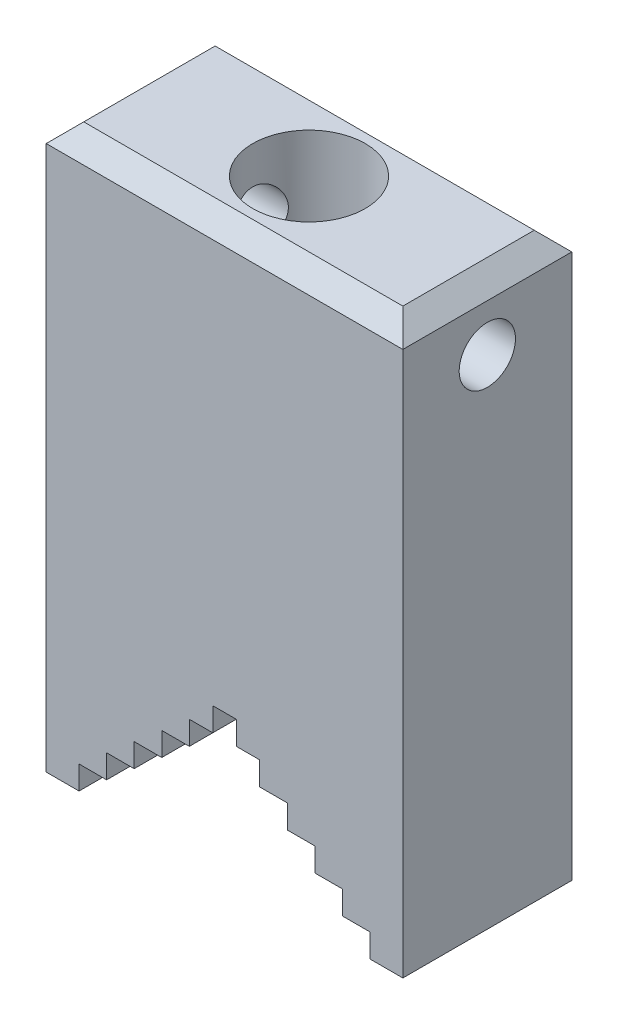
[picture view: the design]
ISO-10303-21;
HEADER;
FILE_DESCRIPTION(('STEP AP214'),'2;1');
FILE_NAME('part.step','',(''),(''),'','','');
FILE_SCHEMA(('AUTOMOTIVE_DESIGN { 1 0 10303 214 1 1 1 1 }'));
ENDSEC;
DATA;
#1=APPLICATION_CONTEXT('core data for automotive mechanical design processes');
#2=APPLICATION_PROTOCOL_DEFINITION('international standard','automotive_design',2000,#1);
#3=PRODUCT_CONTEXT('',#1,'mechanical');
#4=PRODUCT('Part','Part','',(#3));
#5=PRODUCT_RELATED_PRODUCT_CATEGORY('part','',(#4));
#6=PRODUCT_DEFINITION_FORMATION('','',#4);
#7=PRODUCT_DEFINITION_CONTEXT('part definition',#1,'design');
#8=PRODUCT_DEFINITION('design','',#6,#7);
#9=PRODUCT_DEFINITION_SHAPE('','',#8);
#10=(LENGTH_UNIT() NAMED_UNIT(*) SI_UNIT(.MILLI.,.METRE.));
#11=(NAMED_UNIT(*) PLANE_ANGLE_UNIT() SI_UNIT($,.RADIAN.));
#12=(NAMED_UNIT(*) SI_UNIT($,.STERADIAN.) SOLID_ANGLE_UNIT());
#13=UNCERTAINTY_MEASURE_WITH_UNIT(LENGTH_MEASURE(1.E-05),#10,'distance_accuracy_value','');
#14=(GEOMETRIC_REPRESENTATION_CONTEXT(3) GLOBAL_UNCERTAINTY_ASSIGNED_CONTEXT((#13)) GLOBAL_UNIT_ASSIGNED_CONTEXT((#10,
#11,#12)) REPRESENTATION_CONTEXT('',''));
#15=CARTESIAN_POINT('',(0.,0.,0.));
#16=DIRECTION('',(0.,0.,1.));
#17=DIRECTION('',(1.,0.,0.));
#18=AXIS2_PLACEMENT_3D('',#15,#16,#17);
#19=CARTESIAN_POINT('',(-19.,23.,0.));
#20=DIRECTION('',(1.,0.,0.));
#21=DIRECTION('',(0.,1.,0.));
#22=AXIS2_PLACEMENT_3D('',#19,#20,#21);
#23=CYLINDRICAL_SURFACE('',#22,3.);
#24=CARTESIAN_POINT('',(-6.,26.,0.));
#25=CARTESIAN_POINT('',(-5.99999934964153,25.9999991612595,0.07889414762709));
#26=CARTESIAN_POINT('',(-5.99843869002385,25.9968820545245,0.15779662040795));
#27=CARTESIAN_POINT('',(-5.99224358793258,25.98446072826,0.315001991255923));
#28=CARTESIAN_POINT('',(-5.98760776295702,25.9751537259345,0.393304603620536));
#29=CARTESIAN_POINT('',(-5.96921978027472,25.9380421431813,0.626628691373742));
#30=CARTESIAN_POINT('',(-5.95098734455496,25.9010471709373,0.779952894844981));
#31=CARTESIAN_POINT('',(-5.90448966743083,25.8044182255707,1.07683586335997));
#32=CARTESIAN_POINT('',(-5.87626344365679,25.7448722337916,1.22043005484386));
#33=CARTESIAN_POINT('',(-5.81237302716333,25.6052887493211,1.49540820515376));
#34=CARTESIAN_POINT('',(-5.77670942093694,25.5252528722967,1.62679312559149));
#35=CARTESIAN_POINT('',(-5.69868752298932,25.3414460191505,1.88252701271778));
#36=CARTESIAN_POINT('',(-5.65605474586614,25.2365320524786,2.0059694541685));
#37=CARTESIAN_POINT('',(-5.56980033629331,25.0084440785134,2.23433451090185));
#38=CARTESIAN_POINT('',(-5.5261779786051,24.8852562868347,2.3392430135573));
#39=CARTESIAN_POINT('',(-5.43896347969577,24.6125156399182,2.53576864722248));
#40=CARTESIAN_POINT('',(-5.39563602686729,24.4616590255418,2.62572411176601));
#41=CARTESIAN_POINT('',(-5.33782449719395,24.2240491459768,2.7403403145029));
#42=CARTESIAN_POINT('',(-5.31974570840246,24.1429290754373,2.77516786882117));
#43=CARTESIAN_POINT('',(-5.28665768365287,23.9773994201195,2.83769299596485));
#44=CARTESIAN_POINT('',(-5.27164663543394,23.8929918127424,2.86539478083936));
#45=CARTESIAN_POINT('',(-5.24610341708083,23.7266042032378,2.91188280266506));
#46=CARTESIAN_POINT('',(-5.23535838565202,23.6447772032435,2.93110042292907));
#47=CARTESIAN_POINT('',(-5.21757784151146,23.4794450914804,2.9626355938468));
#48=CARTESIAN_POINT('',(-5.21054036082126,23.3959408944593,2.97495680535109));
#49=CARTESIAN_POINT('',(-5.20047756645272,23.2279936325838,2.99251382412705));
#50=CARTESIAN_POINT('',(-5.19744983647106,23.1435511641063,2.99775389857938));
#51=CARTESIAN_POINT('',(-5.19552555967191,22.9745063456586,3.00108452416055));
#52=CARTESIAN_POINT('',(-5.19662861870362,22.8899040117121,2.9991757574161));
#53=CARTESIAN_POINT('',(-5.20534668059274,22.6572461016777,2.98404973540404));
#54=CARTESIAN_POINT('',(-5.21726794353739,22.5097558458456,2.96335042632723));
#55=CARTESIAN_POINT('',(-5.25228182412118,22.2208063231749,2.90082280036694));
#56=CARTESIAN_POINT('',(-5.2753780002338,22.0793489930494,2.85898775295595));
#57=CARTESIAN_POINT('',(-5.33062568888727,21.8023203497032,2.75462843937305));
#58=CARTESIAN_POINT('',(-5.36297559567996,21.6669628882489,2.69164495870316));
#59=CARTESIAN_POINT('',(-5.43310175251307,21.408095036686,2.54712530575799));
#60=CARTESIAN_POINT('',(-5.47088043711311,21.2845900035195,2.46558080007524));
#61=CARTESIAN_POINT('',(-5.55339485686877,21.0364369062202,2.27419808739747));
#62=CARTESIAN_POINT('',(-5.59840533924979,20.9136295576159,2.16208335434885));
#63=CARTESIAN_POINT('',(-5.6864286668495,20.6877935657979,1.91866675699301));
#64=CARTESIAN_POINT('',(-5.72944054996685,20.5847743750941,1.78735577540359));
#65=CARTESIAN_POINT('',(-5.81105962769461,20.3969430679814,1.50154951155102));
#66=CARTESIAN_POINT('',(-5.84936952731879,20.3131985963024,1.3462607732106));
#67=CARTESIAN_POINT('',(-5.91473643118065,20.1737088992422,1.02139864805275));
#68=CARTESIAN_POINT('',(-5.94180236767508,20.1179414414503,0.851836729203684));
#69=CARTESIAN_POINT('',(-5.97973001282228,20.0405737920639,0.518299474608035));
#70=CARTESIAN_POINT('',(-5.99174814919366,20.0165262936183,0.355024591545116));
#71=CARTESIAN_POINT('',(-6.00219040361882,19.9956058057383,0.0263387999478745));
#72=CARTESIAN_POINT('',(-6.00062096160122,19.9987199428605,-0.139071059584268));
#73=CARTESIAN_POINT('',(-5.98473576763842,20.0306200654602,-0.453698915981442));
#74=CARTESIAN_POINT('',(-5.97141737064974,20.0573975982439,-0.603178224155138));
#75=CARTESIAN_POINT('',(-5.93466513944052,20.1327142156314,-0.895220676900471));
#76=CARTESIAN_POINT('',(-5.91123019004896,20.1812556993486,-1.03778305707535));
#77=CARTESIAN_POINT('',(-5.85552754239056,20.2999953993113,-1.31666582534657));
#78=CARTESIAN_POINT('',(-5.82302645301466,20.3707731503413,-1.45269119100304));
#79=CARTESIAN_POINT('',(-5.75231922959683,20.5313226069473,-1.71138408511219));
#80=CARTESIAN_POINT('',(-5.71411066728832,20.6211024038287,-1.83404588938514));
#81=CARTESIAN_POINT('',(-5.63124663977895,20.8272812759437,-2.07530306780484));
#82=CARTESIAN_POINT('',(-5.58632654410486,20.9454286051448,-2.19231623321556));
#83=CARTESIAN_POINT('',(-5.49787174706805,21.1997754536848,-2.40556896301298));
#84=CARTESIAN_POINT('',(-5.45433802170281,21.3359873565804,-2.50179415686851));
#85=CARTESIAN_POINT('',(-5.3715357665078,21.6309309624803,-2.675123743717));
#86=CARTESIAN_POINT('',(-5.33257588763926,21.7904337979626,-2.75107648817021));
#87=CARTESIAN_POINT('',(-5.26722216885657,22.1225302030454,-2.87424847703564));
#88=CARTESIAN_POINT('',(-5.24081214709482,22.2951065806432,-2.92150474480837));
#89=CARTESIAN_POINT('',(-5.2068450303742,22.6307306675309,-2.98158506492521));
#90=CARTESIAN_POINT('',(-5.19772150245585,22.7931027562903,-2.997278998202));
#91=CARTESIAN_POINT('',(-5.19496064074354,23.1183412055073,-3.00206745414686));
#92=CARTESIAN_POINT('',(-5.20131659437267,23.2812073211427,-2.99117350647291));
#93=CARTESIAN_POINT('',(-5.227135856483,23.5864504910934,-2.94577840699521));
#94=CARTESIAN_POINT('',(-5.24529281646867,23.7293013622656,-2.91362505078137));
#95=CARTESIAN_POINT('',(-5.29113050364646,24.0074244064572,-2.82952596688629));
#96=CARTESIAN_POINT('',(-5.3188142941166,24.1426941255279,-2.77757387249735));
#97=CARTESIAN_POINT('',(-5.38285583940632,24.4118743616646,-2.65144766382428));
#98=CARTESIAN_POINT('',(-5.41967139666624,24.5450829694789,-2.57601505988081));
#99=CARTESIAN_POINT('',(-5.49706022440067,24.7978243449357,-2.40645126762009));
#100=CARTESIAN_POINT('',(-5.53763544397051,24.9173499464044,-2.31231035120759));
#101=CARTESIAN_POINT('',(-5.62386853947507,25.1544228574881,-2.094616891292));
#102=CARTESIAN_POINT('',(-5.66954494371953,25.2699651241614,-1.96888052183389));
#103=CARTESIAN_POINT('',(-5.75633712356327,25.478801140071,-1.69843715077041));
#104=CARTESIAN_POINT('',(-5.79745043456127,25.5720828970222,-1.55371998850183));
#105=CARTESIAN_POINT('',(-5.85251406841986,25.6931781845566,-1.32452333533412));
#106=CARTESIAN_POINT('',(-5.86982524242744,25.7305202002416,-1.24575314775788));
#107=CARTESIAN_POINT('',(-5.90168845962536,25.7983616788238,-1.0847972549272));
#108=CARTESIAN_POINT('',(-5.91624185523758,25.8288644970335,-1.00261324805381));
#109=CARTESIAN_POINT('',(-5.94212690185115,25.8826072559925,-0.835616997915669));
#110=CARTESIAN_POINT('',(-5.95346557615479,25.905863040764,-0.750810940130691));
#111=CARTESIAN_POINT('',(-5.97260771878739,25.9448825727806,-0.579142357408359));
#112=CARTESIAN_POINT('',(-5.98041334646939,25.9606508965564,-0.492281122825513));
#113=CARTESIAN_POINT('',(-5.99085829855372,25.9816846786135,-0.337824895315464));
#114=CARTESIAN_POINT('',(-5.99428035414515,25.988546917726,-0.270495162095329));
#115=CARTESIAN_POINT('',(-5.99885151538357,25.997705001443,-0.13544567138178));
#116=CARTESIAN_POINT('',(-6.00000055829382,26.0000007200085,-0.0677259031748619));
#117=CARTESIAN_POINT('',(-6.,26.,0.));
#118=B_SPLINE_CURVE_WITH_KNOTS('',3,(#24,#25,#26,#27,#28,#29,#30,#31,#32,#33,#34,#35,#36,#37,
#38,#39,#40,#41,#42,#43,#44,#45,#46,#47,#48,#49,#50,#51,#52,#53,#54,#55,#56,#57,#58,#59,#60,#61,
#62,#63,#64,#65,#66,#67,#68,#69,#70,#71,#72,#73,#74,#75,#76,#77,#78,#79,#80,#81,#82,#83,#84,#85,
#86,#87,#88,#89,#90,#91,#92,#93,#94,#95,#96,#97,#98,#99,#100,#101,#102,#103,#104,#105,#106,#107,
#108,#109,#110,#111,#112,#113,#114,#115,#116,#117),.UNSPECIFIED.,.T.,.F.,(4,2,2,2,2,2,2,2,2,2,2,
2,2,2,2,2,2,2,2,2,2,2,2,2,2,2,2,2,2,2,2,2,2,2,2,2,2,2,2,2,2,2,2,2,2,2,4),(0.,0.236611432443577,
0.473329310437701,0.947100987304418,1.41904300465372,1.89094781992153,2.39140181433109,
2.89223525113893,3.4319083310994,3.70192714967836,3.97178599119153,4.22563720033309,
4.4793535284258,4.73291689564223,4.98645606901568,5.4323867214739,5.87845946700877,
6.33492255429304,6.79159098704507,7.30616358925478,7.82098138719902,8.35970601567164,
8.89800185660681,9.39171406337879,9.8851922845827,10.3404225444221,10.7957029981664,
11.2640010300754,11.7324988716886,12.2470036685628,12.7618630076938,13.3016558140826,
13.8407507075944,14.3280945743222,14.8152271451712,15.2559532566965,15.6968212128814,
16.1673090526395,16.6380421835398,17.1659726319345,17.6941868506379,17.9605054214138,
18.2266930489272,18.4922945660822,18.7577335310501,18.9608446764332,19.1639614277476),.UNSPECIFIED.);
#119=CARTESIAN_POINT('',(-6.,26.,0.));
#120=VERTEX_POINT('',#119);
#121=EDGE_CURVE('E270',#120,#120,#118,.T.);
#122=ORIENTED_EDGE('',*,*,#121,.T.);
#123=EDGE_LOOP('',(#122));
#124=FACE_BOUND('',#123,.T.);
#125=CARTESIAN_POINT('',(-19.,23.,0.));
#126=DIRECTION('',(1.,0.,0.));
#127=DIRECTION('',(0.,1.,0.));
#128=AXIS2_PLACEMENT_3D('',#125,#126,#127);
#129=CIRCLE('',#128,3.);
#130=CARTESIAN_POINT('',(-19.,26.,0.));
#131=VERTEX_POINT('',#130);
#132=EDGE_CURVE('E269',#131,#131,#129,.T.);
#133=ORIENTED_EDGE('',*,*,#132,.F.);
#134=EDGE_LOOP('',(#133));
#135=FACE_BOUND('',#134,.T.);
#136=ADVANCED_FACE('F26',(#124,#135),#23,.F.);
#137=CARTESIAN_POINT('',(-19.,30.,9.));
#138=DIRECTION('',(1.,0.,0.));
#139=DIRECTION('',(0.,1.,0.));
#140=AXIS2_PLACEMENT_3D('',#137,#138,#139);
#141=PLANE('',#140);
#142=ORIENTED_EDGE('',*,*,#132,.T.);
#143=EDGE_LOOP('',(#142));
#144=FACE_BOUND('',#143,.T.);
#145=DIRECTION('',(0.,-1.,0.));
#146=VECTOR('',#145,1.);
#147=CARTESIAN_POINT('',(-19.,30.,9.));
#148=LINE('',#147,#146);
#149=CARTESIAN_POINT('',(-19.,28.,9.));
#150=VERTEX_POINT('',#149);
#151=CARTESIAN_POINT('',(-19.,-30.,9.));
#152=VERTEX_POINT('',#151);
#153=EDGE_CURVE('E333',#150,#152,#148,.T.);
#154=ORIENTED_EDGE('',*,*,#153,.F.);
#155=DIRECTION('',(0.,0.,-1.));
#156=VECTOR('',#155,1.);
#157=CARTESIAN_POINT('',(-19.,28.,9.));
#158=LINE('',#157,#156);
#159=CARTESIAN_POINT('',(-19.,28.,-9.));
#160=VERTEX_POINT('',#159);
#161=EDGE_CURVE('E465',#150,#160,#158,.T.);
#162=ORIENTED_EDGE('',*,*,#161,.T.);
#163=DIRECTION('',(0.,-1.,0.));
#164=VECTOR('',#163,1.);
#165=CARTESIAN_POINT('',(-19.,30.,-9.));
#166=LINE('',#165,#164);
#167=CARTESIAN_POINT('',(-19.,-30.,-9.));
#168=VERTEX_POINT('',#167);
#169=EDGE_CURVE('E273',#160,#168,#166,.T.);
#170=ORIENTED_EDGE('',*,*,#169,.T.);
#171=DIRECTION('',(0.,0.,-1.));
#172=VECTOR('',#171,1.);
#173=CARTESIAN_POINT('',(-19.,-30.,9.));
#174=LINE('',#173,#172);
#175=EDGE_CURVE('E462',#152,#168,#174,.T.);
#176=ORIENTED_EDGE('',*,*,#175,.F.);
#177=EDGE_LOOP('',(#154,#162,#170,#176));
#178=FACE_BOUND('',#177,.T.);
#179=ADVANCED_FACE('F28',(#144,#178),#141,.F.);
#180=CARTESIAN_POINT('',(-19.,-30.,9.));
#181=DIRECTION('',(0.,1.,0.));
#182=DIRECTION('',(0.,0.,1.));
#183=AXIS2_PLACEMENT_3D('',#180,#181,#182);
#184=PLANE('',#183);
#185=DIRECTION('',(1.,0.,0.));
#186=VECTOR('',#185,1.);
#187=CARTESIAN_POINT('',(-19.,-30.,-9.));
#188=LINE('',#187,#186);
#189=CARTESIAN_POINT('',(-15.5,-30.,-9.));
#190=VERTEX_POINT('',#189);
#191=EDGE_CURVE('E281',#168,#190,#188,.T.);
#192=ORIENTED_EDGE('',*,*,#191,.T.);
#193=DIRECTION('',(0.,0.,-1.));
#194=VECTOR('',#193,1.);
#195=CARTESIAN_POINT('',(-15.5,-30.,9.));
#196=LINE('',#195,#194);
#197=CARTESIAN_POINT('',(-15.5,-30.,9.));
#198=VERTEX_POINT('',#197);
#199=EDGE_CURVE('E459',#198,#190,#196,.T.);
#200=ORIENTED_EDGE('',*,*,#199,.F.);
#201=DIRECTION('',(1.,0.,0.));
#202=VECTOR('',#201,1.);
#203=CARTESIAN_POINT('',(-19.,-30.,9.));
#204=LINE('',#203,#202);
#205=EDGE_CURVE('E335',#152,#198,#204,.T.);
#206=ORIENTED_EDGE('',*,*,#205,.F.);
#207=ORIENTED_EDGE('',*,*,#175,.T.);
#208=EDGE_LOOP('',(#192,#200,#206,#207));
#209=FACE_BOUND('',#208,.T.);
#210=ADVANCED_FACE('F248',(#209),#184,.F.);
#211=CARTESIAN_POINT('',(-15.5,-30.,9.));
#212=DIRECTION('',(-1.,0.,0.));
#213=DIRECTION('',(0.,-1.,0.));
#214=AXIS2_PLACEMENT_3D('',#211,#212,#213);
#215=PLANE('',#214);
#216=DIRECTION('',(0.,1.,0.));
#217=VECTOR('',#216,1.);
#218=CARTESIAN_POINT('',(-15.5,-30.,-9.));
#219=LINE('',#218,#217);
#220=CARTESIAN_POINT('',(-15.5,-27.5,-9.));
#221=VERTEX_POINT('',#220);
#222=EDGE_CURVE('E283',#190,#221,#219,.T.);
#223=ORIENTED_EDGE('',*,*,#222,.T.);
#224=DIRECTION('',(0.,0.,-1.));
#225=VECTOR('',#224,1.);
#226=CARTESIAN_POINT('',(-15.5,-27.5,9.));
#227=LINE('',#226,#225);
#228=CARTESIAN_POINT('',(-15.5,-27.5,9.));
#229=VERTEX_POINT('',#228);
#230=EDGE_CURVE('E456',#229,#221,#227,.T.);
#231=ORIENTED_EDGE('',*,*,#230,.F.);
#232=DIRECTION('',(0.,1.,0.));
#233=VECTOR('',#232,1.);
#234=CARTESIAN_POINT('',(-15.5,-30.,9.));
#235=LINE('',#234,#233);
#236=EDGE_CURVE('E337',#198,#229,#235,.T.);
#237=ORIENTED_EDGE('',*,*,#236,.F.);
#238=ORIENTED_EDGE('',*,*,#199,.T.);
#239=EDGE_LOOP('',(#223,#231,#237,#238));
#240=FACE_BOUND('',#239,.T.);
#241=ADVANCED_FACE('F618',(#240),#215,.F.);
#242=CARTESIAN_POINT('',(-15.5,-27.5,9.));
#243=DIRECTION('',(0.,1.,0.));
#244=DIRECTION('',(0.,0.,1.));
#245=AXIS2_PLACEMENT_3D('',#242,#243,#244);
#246=PLANE('',#245);
#247=DIRECTION('',(1.,0.,0.));
#248=VECTOR('',#247,1.);
#249=CARTESIAN_POINT('',(-15.5,-27.5,-9.));
#250=LINE('',#249,#248);
#251=CARTESIAN_POINT('',(-12.5625,-27.5,-9.));
#252=VERTEX_POINT('',#251);
#253=EDGE_CURVE('E285',#221,#252,#250,.T.);
#254=ORIENTED_EDGE('',*,*,#253,.T.);
#255=DIRECTION('',(0.,0.,-1.));
#256=VECTOR('',#255,1.);
#257=CARTESIAN_POINT('',(-12.5625,-27.5,9.));
#258=LINE('',#257,#256);
#259=CARTESIAN_POINT('',(-12.5625,-27.5,9.));
#260=VERTEX_POINT('',#259);
#261=EDGE_CURVE('E453',#260,#252,#258,.T.);
#262=ORIENTED_EDGE('',*,*,#261,.F.);
#263=DIRECTION('',(1.,0.,0.));
#264=VECTOR('',#263,1.);
#265=CARTESIAN_POINT('',(-15.5,-27.5,9.));
#266=LINE('',#265,#264);
#267=EDGE_CURVE('E339',#229,#260,#266,.T.);
#268=ORIENTED_EDGE('',*,*,#267,.F.);
#269=ORIENTED_EDGE('',*,*,#230,.T.);
#270=EDGE_LOOP('',(#254,#262,#268,#269));
#271=FACE_BOUND('',#270,.T.);
#272=ADVANCED_FACE('F614',(#271),#246,.F.);
#273=CARTESIAN_POINT('',(-12.5625,-27.5,9.));
#274=DIRECTION('',(-1.,0.,0.));
#275=DIRECTION('',(0.,0.,1.));
#276=AXIS2_PLACEMENT_3D('',#273,#274,#275);
#277=PLANE('',#276);
#278=DIRECTION('',(0.,1.,0.));
#279=VECTOR('',#278,1.);
#280=CARTESIAN_POINT('',(-12.5625,-27.5,-9.));
#281=LINE('',#280,#279);
#282=CARTESIAN_POINT('',(-12.5625,-25.,-9.));
#283=VERTEX_POINT('',#282);
#284=EDGE_CURVE('E287',#252,#283,#281,.T.);
#285=ORIENTED_EDGE('',*,*,#284,.T.);
#286=DIRECTION('',(0.,0.,-1.));
#287=VECTOR('',#286,1.);
#288=CARTESIAN_POINT('',(-12.5625,-25.,9.));
#289=LINE('',#288,#287);
#290=CARTESIAN_POINT('',(-12.5625,-25.,9.));
#291=VERTEX_POINT('',#290);
#292=EDGE_CURVE('E450',#291,#283,#289,.T.);
#293=ORIENTED_EDGE('',*,*,#292,.F.);
#294=DIRECTION('',(0.,1.,0.));
#295=VECTOR('',#294,1.);
#296=CARTESIAN_POINT('',(-12.5625,-27.5,9.));
#297=LINE('',#296,#295);
#298=EDGE_CURVE('E341',#260,#291,#297,.T.);
#299=ORIENTED_EDGE('',*,*,#298,.F.);
#300=ORIENTED_EDGE('',*,*,#261,.T.);
#301=EDGE_LOOP('',(#285,#293,#299,#300));
#302=FACE_BOUND('',#301,.T.);
#303=ADVANCED_FACE('F610',(#302),#277,.F.);
#304=CARTESIAN_POINT('',(-12.5625,-25.,9.));
#305=DIRECTION('',(0.,1.,0.));
#306=DIRECTION('',(0.,0.,1.));
#307=AXIS2_PLACEMENT_3D('',#304,#305,#306);
#308=PLANE('',#307);
#309=DIRECTION('',(1.,0.,0.));
#310=VECTOR('',#309,1.);
#311=CARTESIAN_POINT('',(-12.5625,-25.,-9.));
#312=LINE('',#311,#310);
#313=CARTESIAN_POINT('',(-9.625,-25.,-9.));
#314=VERTEX_POINT('',#313);
#315=EDGE_CURVE('E289',#283,#314,#312,.T.);
#316=ORIENTED_EDGE('',*,*,#315,.T.);
#317=DIRECTION('',(0.,0.,-1.));
#318=VECTOR('',#317,1.);
#319=CARTESIAN_POINT('',(-9.625,-25.,9.));
#320=LINE('',#319,#318);
#321=CARTESIAN_POINT('',(-9.625,-25.,9.));
#322=VERTEX_POINT('',#321);
#323=EDGE_CURVE('E447',#322,#314,#320,.T.);
#324=ORIENTED_EDGE('',*,*,#323,.F.);
#325=DIRECTION('',(1.,0.,0.));
#326=VECTOR('',#325,1.);
#327=CARTESIAN_POINT('',(-12.5625,-25.,9.));
#328=LINE('',#327,#326);
#329=EDGE_CURVE('E343',#291,#322,#328,.T.);
#330=ORIENTED_EDGE('',*,*,#329,.F.);
#331=ORIENTED_EDGE('',*,*,#292,.T.);
#332=EDGE_LOOP('',(#316,#324,#330,#331));
#333=FACE_BOUND('',#332,.T.);
#334=ADVANCED_FACE('F606',(#333),#308,.F.);
#335=CARTESIAN_POINT('',(-9.625,-25.,9.));
#336=DIRECTION('',(-1.,0.,0.));
#337=DIRECTION('',(0.,0.,1.));
#338=AXIS2_PLACEMENT_3D('',#335,#336,#337);
#339=PLANE('',#338);
#340=DIRECTION('',(0.,1.,0.));
#341=VECTOR('',#340,1.);
#342=CARTESIAN_POINT('',(-9.625,-25.,-9.));
#343=LINE('',#342,#341);
#344=CARTESIAN_POINT('',(-9.625,-22.5,-9.));
#345=VERTEX_POINT('',#344);
#346=EDGE_CURVE('E291',#314,#345,#343,.T.);
#347=ORIENTED_EDGE('',*,*,#346,.T.);
#348=DIRECTION('',(0.,0.,-1.));
#349=VECTOR('',#348,1.);
#350=CARTESIAN_POINT('',(-9.625,-22.5,9.));
#351=LINE('',#350,#349);
#352=CARTESIAN_POINT('',(-9.625,-22.5,9.));
#353=VERTEX_POINT('',#352);
#354=EDGE_CURVE('E444',#353,#345,#351,.T.);
#355=ORIENTED_EDGE('',*,*,#354,.F.);
#356=DIRECTION('',(0.,1.,0.));
#357=VECTOR('',#356,1.);
#358=CARTESIAN_POINT('',(-9.625,-25.,9.));
#359=LINE('',#358,#357);
#360=EDGE_CURVE('E345',#322,#353,#359,.T.);
#361=ORIENTED_EDGE('',*,*,#360,.F.);
#362=ORIENTED_EDGE('',*,*,#323,.T.);
#363=EDGE_LOOP('',(#347,#355,#361,#362));
#364=FACE_BOUND('',#363,.T.);
#365=ADVANCED_FACE('F602',(#364),#339,.F.);
#366=CARTESIAN_POINT('',(-9.625,-22.5,9.));
#367=DIRECTION('',(0.,1.,0.));
#368=DIRECTION('',(0.,0.,1.));
#369=AXIS2_PLACEMENT_3D('',#366,#367,#368);
#370=PLANE('',#369);
#371=DIRECTION('',(1.,0.,0.));
#372=VECTOR('',#371,1.);
#373=CARTESIAN_POINT('',(-9.625,-22.5,-9.));
#374=LINE('',#373,#372);
#375=CARTESIAN_POINT('',(-6.6875,-22.5,-9.));
#376=VERTEX_POINT('',#375);
#377=EDGE_CURVE('E293',#345,#376,#374,.T.);
#378=ORIENTED_EDGE('',*,*,#377,.T.);
#379=DIRECTION('',(0.,0.,-1.));
#380=VECTOR('',#379,1.);
#381=CARTESIAN_POINT('',(-6.6875,-22.5,9.));
#382=LINE('',#381,#380);
#383=CARTESIAN_POINT('',(-6.6875,-22.5,9.));
#384=VERTEX_POINT('',#383);
#385=EDGE_CURVE('E441',#384,#376,#382,.T.);
#386=ORIENTED_EDGE('',*,*,#385,.F.);
#387=DIRECTION('',(1.,0.,0.));
#388=VECTOR('',#387,1.);
#389=CARTESIAN_POINT('',(-9.625,-22.5,9.));
#390=LINE('',#389,#388);
#391=EDGE_CURVE('E347',#353,#384,#390,.T.);
#392=ORIENTED_EDGE('',*,*,#391,.F.);
#393=ORIENTED_EDGE('',*,*,#354,.T.);
#394=EDGE_LOOP('',(#378,#386,#392,#393));
#395=FACE_BOUND('',#394,.T.);
#396=ADVANCED_FACE('F598',(#395),#370,.F.);
#397=CARTESIAN_POINT('',(-6.6875,-22.5,9.));
#398=DIRECTION('',(-1.,0.,0.));
#399=DIRECTION('',(0.,-1.,0.));
#400=AXIS2_PLACEMENT_3D('',#397,#398,#399);
#401=PLANE('',#400);
#402=DIRECTION('',(0.,1.,0.));
#403=VECTOR('',#402,1.);
#404=CARTESIAN_POINT('',(-6.6875,-22.5,-9.));
#405=LINE('',#404,#403);
#406=CARTESIAN_POINT('',(-6.6875,-20.,-9.));
#407=VERTEX_POINT('',#406);
#408=EDGE_CURVE('E295',#376,#407,#405,.T.);
#409=ORIENTED_EDGE('',*,*,#408,.T.);
#410=DIRECTION('',(0.,0.,-1.));
#411=VECTOR('',#410,1.);
#412=CARTESIAN_POINT('',(-6.6875,-20.,9.));
#413=LINE('',#412,#411);
#414=CARTESIAN_POINT('',(-6.6875,-20.,9.));
#415=VERTEX_POINT('',#414);
#416=EDGE_CURVE('E438',#415,#407,#413,.T.);
#417=ORIENTED_EDGE('',*,*,#416,.F.);
#418=DIRECTION('',(0.,1.,0.));
#419=VECTOR('',#418,1.);
#420=CARTESIAN_POINT('',(-6.6875,-22.5,9.));
#421=LINE('',#420,#419);
#422=EDGE_CURVE('E349',#384,#415,#421,.T.);
#423=ORIENTED_EDGE('',*,*,#422,.F.);
#424=ORIENTED_EDGE('',*,*,#385,.T.);
#425=EDGE_LOOP('',(#409,#417,#423,#424));
#426=FACE_BOUND('',#425,.T.);
#427=ADVANCED_FACE('F594',(#426),#401,.F.);
#428=CARTESIAN_POINT('',(-6.6875,-20.,9.));
#429=DIRECTION('',(0.,1.,0.));
#430=DIRECTION('',(-1.,0.,0.));
#431=AXIS2_PLACEMENT_3D('',#428,#429,#430);
#432=PLANE('',#431);
#433=DIRECTION('',(1.,0.,0.));
#434=VECTOR('',#433,1.);
#435=CARTESIAN_POINT('',(-6.6875,-20.,-9.));
#436=LINE('',#435,#434);
#437=CARTESIAN_POINT('',(-3.74999999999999,-20.,-9.));
#438=VERTEX_POINT('',#437);
#439=EDGE_CURVE('E297',#407,#438,#436,.T.);
#440=ORIENTED_EDGE('',*,*,#439,.T.);
#441=DIRECTION('',(0.,0.,-1.));
#442=VECTOR('',#441,1.);
#443=CARTESIAN_POINT('',(-3.74999999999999,-20.,9.));
#444=LINE('',#443,#442);
#445=CARTESIAN_POINT('',(-3.74999999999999,-20.,9.));
#446=VERTEX_POINT('',#445);
#447=EDGE_CURVE('E435',#446,#438,#444,.T.);
#448=ORIENTED_EDGE('',*,*,#447,.F.);
#449=DIRECTION('',(1.,0.,0.));
#450=VECTOR('',#449,1.);
#451=CARTESIAN_POINT('',(-6.6875,-20.,9.));
#452=LINE('',#451,#450);
#453=EDGE_CURVE('E351',#415,#446,#452,.T.);
#454=ORIENTED_EDGE('',*,*,#453,.F.);
#455=ORIENTED_EDGE('',*,*,#416,.T.);
#456=EDGE_LOOP('',(#440,#448,#454,#455));
#457=FACE_BOUND('',#456,.T.);
#458=ADVANCED_FACE('F590',(#457),#432,.F.);
#459=CARTESIAN_POINT('',(-3.74999999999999,-20.,9.));
#460=DIRECTION('',(-1.,0.,0.));
#461=DIRECTION('',(0.,-1.,0.));
#462=AXIS2_PLACEMENT_3D('',#459,#460,#461);
#463=PLANE('',#462);
#464=DIRECTION('',(0.,1.,0.));
#465=VECTOR('',#464,1.);
#466=CARTESIAN_POINT('',(-3.74999999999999,-20.,-9.));
#467=LINE('',#466,#465);
#468=CARTESIAN_POINT('',(-3.74999999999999,-17.5,-9.));
#469=VERTEX_POINT('',#468);
#470=EDGE_CURVE('E299',#438,#469,#467,.T.);
#471=ORIENTED_EDGE('',*,*,#470,.T.);
#472=DIRECTION('',(0.,0.,-1.));
#473=VECTOR('',#472,1.);
#474=CARTESIAN_POINT('',(-3.74999999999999,-17.5,9.));
#475=LINE('',#474,#473);
#476=CARTESIAN_POINT('',(-3.74999999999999,-17.5,9.));
#477=VERTEX_POINT('',#476);
#478=EDGE_CURVE('E432',#477,#469,#475,.T.);
#479=ORIENTED_EDGE('',*,*,#478,.F.);
#480=DIRECTION('',(0.,1.,0.));
#481=VECTOR('',#480,1.);
#482=CARTESIAN_POINT('',(-3.74999999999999,-20.,9.));
#483=LINE('',#482,#481);
#484=EDGE_CURVE('E353',#446,#477,#483,.T.);
#485=ORIENTED_EDGE('',*,*,#484,.F.);
#486=ORIENTED_EDGE('',*,*,#447,.T.);
#487=EDGE_LOOP('',(#471,#479,#485,#486));
#488=FACE_BOUND('',#487,.T.);
#489=ADVANCED_FACE('F586',(#488),#463,.F.);
#490=CARTESIAN_POINT('',(-3.74999999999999,-17.5,9.));
#491=DIRECTION('',(0.,1.,0.));
#492=DIRECTION('',(0.,0.,1.));
#493=AXIS2_PLACEMENT_3D('',#490,#491,#492);
#494=PLANE('',#493);
#495=DIRECTION('',(1.,0.,0.));
#496=VECTOR('',#495,1.);
#497=CARTESIAN_POINT('',(-3.74999999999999,-17.5,-9.));
#498=LINE('',#497,#496);
#499=CARTESIAN_POINT('',(-1.25,-17.5,-9.));
#500=VERTEX_POINT('',#499);
#501=EDGE_CURVE('E301',#469,#500,#498,.T.);
#502=ORIENTED_EDGE('',*,*,#501,.T.);
#503=DIRECTION('',(0.,0.,-1.));
#504=VECTOR('',#503,1.);
#505=CARTESIAN_POINT('',(-1.25,-17.5,9.));
#506=LINE('',#505,#504);
#507=CARTESIAN_POINT('',(-1.25,-17.5,9.));
#508=VERTEX_POINT('',#507);
#509=EDGE_CURVE('E429',#508,#500,#506,.T.);
#510=ORIENTED_EDGE('',*,*,#509,.F.);
#511=DIRECTION('',(1.,0.,0.));
#512=VECTOR('',#511,1.);
#513=CARTESIAN_POINT('',(-3.74999999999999,-17.5,9.));
#514=LINE('',#513,#512);
#515=EDGE_CURVE('E355',#477,#508,#514,.T.);
#516=ORIENTED_EDGE('',*,*,#515,.F.);
#517=ORIENTED_EDGE('',*,*,#478,.T.);
#518=EDGE_LOOP('',(#502,#510,#516,#517));
#519=FACE_BOUND('',#518,.T.);
#520=ADVANCED_FACE('F582',(#519),#494,.F.);
#521=CARTESIAN_POINT('',(-1.25,-17.5,9.));
#522=DIRECTION('',(-1.,0.,0.));
#523=DIRECTION('',(0.,-1.,0.));
#524=AXIS2_PLACEMENT_3D('',#521,#522,#523);
#525=PLANE('',#524);
#526=DIRECTION('',(0.,1.,0.));
#527=VECTOR('',#526,1.);
#528=CARTESIAN_POINT('',(-1.25,-17.5,-9.));
#529=LINE('',#528,#527);
#530=CARTESIAN_POINT('',(-1.25,-15.,-9.));
#531=VERTEX_POINT('',#530);
#532=EDGE_CURVE('E303',#500,#531,#529,.T.);
#533=ORIENTED_EDGE('',*,*,#532,.T.);
#534=DIRECTION('',(0.,0.,-1.));
#535=VECTOR('',#534,1.);
#536=CARTESIAN_POINT('',(-1.25,-15.,9.));
#537=LINE('',#536,#535);
#538=CARTESIAN_POINT('',(-1.25,-15.,9.));
#539=VERTEX_POINT('',#538);
#540=EDGE_CURVE('E426',#539,#531,#537,.T.);
#541=ORIENTED_EDGE('',*,*,#540,.F.);
#542=DIRECTION('',(0.,1.,0.));
#543=VECTOR('',#542,1.);
#544=CARTESIAN_POINT('',(-1.25,-17.5,9.));
#545=LINE('',#544,#543);
#546=EDGE_CURVE('E357',#508,#539,#545,.T.);
#547=ORIENTED_EDGE('',*,*,#546,.F.);
#548=ORIENTED_EDGE('',*,*,#509,.T.);
#549=EDGE_LOOP('',(#533,#541,#547,#548));
#550=FACE_BOUND('',#549,.T.);
#551=ADVANCED_FACE('F578',(#550),#525,.F.);
#552=CARTESIAN_POINT('',(-1.25,-15.,9.));
#553=DIRECTION('',(0.,1.,0.));
#554=DIRECTION('',(0.,0.,1.));
#555=AXIS2_PLACEMENT_3D('',#552,#553,#554);
#556=PLANE('',#555);
#557=DIRECTION('',(1.,0.,0.));
#558=VECTOR('',#557,1.);
#559=CARTESIAN_POINT('',(-1.25,-15.,-9.));
#560=LINE('',#559,#558);
#561=CARTESIAN_POINT('',(1.25,-15.,-9.));
#562=VERTEX_POINT('',#561);
#563=EDGE_CURVE('E305',#531,#562,#560,.T.);
#564=ORIENTED_EDGE('',*,*,#563,.T.);
#565=DIRECTION('',(0.,0.,-1.));
#566=VECTOR('',#565,1.);
#567=CARTESIAN_POINT('',(1.25,-15.,9.));
#568=LINE('',#567,#566);
#569=CARTESIAN_POINT('',(1.25,-15.,9.));
#570=VERTEX_POINT('',#569);
#571=EDGE_CURVE('E423',#570,#562,#568,.T.);
#572=ORIENTED_EDGE('',*,*,#571,.F.);
#573=DIRECTION('',(1.,0.,0.));
#574=VECTOR('',#573,1.);
#575=CARTESIAN_POINT('',(-1.25,-15.,9.));
#576=LINE('',#575,#574);
#577=EDGE_CURVE('E359',#539,#570,#576,.T.);
#578=ORIENTED_EDGE('',*,*,#577,.F.);
#579=ORIENTED_EDGE('',*,*,#540,.T.);
#580=EDGE_LOOP('',(#564,#572,#578,#579));
#581=FACE_BOUND('',#580,.T.);
#582=ADVANCED_FACE('F574',(#581),#556,.F.);
#583=CARTESIAN_POINT('',(1.25,-17.5,9.));
#584=DIRECTION('',(1.,0.,0.));
#585=DIRECTION('',(0.,1.,0.));
#586=AXIS2_PLACEMENT_3D('',#583,#584,#585);
#587=PLANE('',#586);
#588=DIRECTION('',(0.,-1.,0.));
#589=VECTOR('',#588,1.);
#590=CARTESIAN_POINT('',(1.25,-17.5,-9.));
#591=LINE('',#590,#589);
#592=CARTESIAN_POINT('',(1.25,-17.5,-9.));
#593=VERTEX_POINT('',#592);
#594=EDGE_CURVE('E307',#562,#593,#591,.T.);
#595=ORIENTED_EDGE('',*,*,#594,.T.);
#596=DIRECTION('',(0.,0.,-1.));
#597=VECTOR('',#596,1.);
#598=CARTESIAN_POINT('',(1.25,-17.5,9.));
#599=LINE('',#598,#597);
#600=CARTESIAN_POINT('',(1.25,-17.5,9.));
#601=VERTEX_POINT('',#600);
#602=EDGE_CURVE('E420',#601,#593,#599,.T.);
#603=ORIENTED_EDGE('',*,*,#602,.F.);
#604=DIRECTION('',(0.,-1.,0.));
#605=VECTOR('',#604,1.);
#606=CARTESIAN_POINT('',(1.25,-17.5,9.));
#607=LINE('',#606,#605);
#608=EDGE_CURVE('E361',#570,#601,#607,.T.);
#609=ORIENTED_EDGE('',*,*,#608,.F.);
#610=ORIENTED_EDGE('',*,*,#571,.T.);
#611=EDGE_LOOP('',(#595,#603,#609,#610));
#612=FACE_BOUND('',#611,.T.);
#613=ADVANCED_FACE('F570',(#612),#587,.F.);
#614=CARTESIAN_POINT('',(3.75,-17.5,9.));
#615=DIRECTION('',(0.,1.,0.));
#616=DIRECTION('',(0.,0.,1.));
#617=AXIS2_PLACEMENT_3D('',#614,#615,#616);
#618=PLANE('',#617);
#619=DIRECTION('',(1.,0.,0.));
#620=VECTOR('',#619,1.);
#621=CARTESIAN_POINT('',(3.75,-17.5,-9.));
#622=LINE('',#621,#620);
#623=CARTESIAN_POINT('',(3.75,-17.5,-9.));
#624=VERTEX_POINT('',#623);
#625=EDGE_CURVE('E309',#593,#624,#622,.T.);
#626=ORIENTED_EDGE('',*,*,#625,.T.);
#627=DIRECTION('',(0.,0.,-1.));
#628=VECTOR('',#627,1.);
#629=CARTESIAN_POINT('',(3.75,-17.5,9.));
#630=LINE('',#629,#628);
#631=CARTESIAN_POINT('',(3.75,-17.5,9.));
#632=VERTEX_POINT('',#631);
#633=EDGE_CURVE('E417',#632,#624,#630,.T.);
#634=ORIENTED_EDGE('',*,*,#633,.F.);
#635=DIRECTION('',(1.,0.,0.));
#636=VECTOR('',#635,1.);
#637=CARTESIAN_POINT('',(3.75,-17.5,9.));
#638=LINE('',#637,#636);
#639=EDGE_CURVE('E363',#601,#632,#638,.T.);
#640=ORIENTED_EDGE('',*,*,#639,.F.);
#641=ORIENTED_EDGE('',*,*,#602,.T.);
#642=EDGE_LOOP('',(#626,#634,#640,#641));
#643=FACE_BOUND('',#642,.T.);
#644=ADVANCED_FACE('F566',(#643),#618,.F.);
#645=CARTESIAN_POINT('',(3.75,-20.,9.));
#646=DIRECTION('',(1.,0.,0.));
#647=DIRECTION('',(0.,1.,0.));
#648=AXIS2_PLACEMENT_3D('',#645,#646,#647);
#649=PLANE('',#648);
#650=DIRECTION('',(0.,-1.,0.));
#651=VECTOR('',#650,1.);
#652=CARTESIAN_POINT('',(3.75,-20.,-9.));
#653=LINE('',#652,#651);
#654=CARTESIAN_POINT('',(3.75,-20.,-9.));
#655=VERTEX_POINT('',#654);
#656=EDGE_CURVE('E311',#624,#655,#653,.T.);
#657=ORIENTED_EDGE('',*,*,#656,.T.);
#658=DIRECTION('',(0.,0.,-1.));
#659=VECTOR('',#658,1.);
#660=CARTESIAN_POINT('',(3.75,-20.,9.));
#661=LINE('',#660,#659);
#662=CARTESIAN_POINT('',(3.75,-20.,9.));
#663=VERTEX_POINT('',#662);
#664=EDGE_CURVE('E414',#663,#655,#661,.T.);
#665=ORIENTED_EDGE('',*,*,#664,.F.);
#666=DIRECTION('',(0.,-1.,0.));
#667=VECTOR('',#666,1.);
#668=CARTESIAN_POINT('',(3.75,-20.,9.));
#669=LINE('',#668,#667);
#670=EDGE_CURVE('E365',#632,#663,#669,.T.);
#671=ORIENTED_EDGE('',*,*,#670,.F.);
#672=ORIENTED_EDGE('',*,*,#633,.T.);
#673=EDGE_LOOP('',(#657,#665,#671,#672));
#674=FACE_BOUND('',#673,.T.);
#675=ADVANCED_FACE('F562',(#674),#649,.F.);
#676=CARTESIAN_POINT('',(6.6875,-20.,9.));
#677=DIRECTION('',(0.,1.,0.));
#678=DIRECTION('',(-1.,0.,0.));
#679=AXIS2_PLACEMENT_3D('',#676,#677,#678);
#680=PLANE('',#679);
#681=DIRECTION('',(1.,0.,0.));
#682=VECTOR('',#681,1.);
#683=CARTESIAN_POINT('',(6.6875,-20.,-9.));
#684=LINE('',#683,#682);
#685=CARTESIAN_POINT('',(6.6875,-20.,-9.));
#686=VERTEX_POINT('',#685);
#687=EDGE_CURVE('E313',#655,#686,#684,.T.);
#688=ORIENTED_EDGE('',*,*,#687,.T.);
#689=DIRECTION('',(0.,0.,-1.));
#690=VECTOR('',#689,1.);
#691=CARTESIAN_POINT('',(6.6875,-20.,9.));
#692=LINE('',#691,#690);
#693=CARTESIAN_POINT('',(6.6875,-20.,9.));
#694=VERTEX_POINT('',#693);
#695=EDGE_CURVE('E411',#694,#686,#692,.T.);
#696=ORIENTED_EDGE('',*,*,#695,.F.);
#697=DIRECTION('',(1.,0.,0.));
#698=VECTOR('',#697,1.);
#699=CARTESIAN_POINT('',(6.6875,-20.,9.));
#700=LINE('',#699,#698);
#701=EDGE_CURVE('E367',#663,#694,#700,.T.);
#702=ORIENTED_EDGE('',*,*,#701,.F.);
#703=ORIENTED_EDGE('',*,*,#664,.T.);
#704=EDGE_LOOP('',(#688,#696,#702,#703));
#705=FACE_BOUND('',#704,.T.);
#706=ADVANCED_FACE('F558',(#705),#680,.F.);
#707=CARTESIAN_POINT('',(6.6875,-22.5,9.));
#708=DIRECTION('',(1.,0.,0.));
#709=DIRECTION('',(0.,1.,0.));
#710=AXIS2_PLACEMENT_3D('',#707,#708,#709);
#711=PLANE('',#710);
#712=DIRECTION('',(0.,-1.,0.));
#713=VECTOR('',#712,1.);
#714=CARTESIAN_POINT('',(6.6875,-22.5,-9.));
#715=LINE('',#714,#713);
#716=CARTESIAN_POINT('',(6.6875,-22.5,-9.));
#717=VERTEX_POINT('',#716);
#718=EDGE_CURVE('E315',#686,#717,#715,.T.);
#719=ORIENTED_EDGE('',*,*,#718,.T.);
#720=DIRECTION('',(0.,0.,-1.));
#721=VECTOR('',#720,1.);
#722=CARTESIAN_POINT('',(6.6875,-22.5,9.));
#723=LINE('',#722,#721);
#724=CARTESIAN_POINT('',(6.6875,-22.5,9.));
#725=VERTEX_POINT('',#724);
#726=EDGE_CURVE('E408',#725,#717,#723,.T.);
#727=ORIENTED_EDGE('',*,*,#726,.F.);
#728=DIRECTION('',(0.,-1.,0.));
#729=VECTOR('',#728,1.);
#730=CARTESIAN_POINT('',(6.6875,-22.5,9.));
#731=LINE('',#730,#729);
#732=EDGE_CURVE('E369',#694,#725,#731,.T.);
#733=ORIENTED_EDGE('',*,*,#732,.F.);
#734=ORIENTED_EDGE('',*,*,#695,.T.);
#735=EDGE_LOOP('',(#719,#727,#733,#734));
#736=FACE_BOUND('',#735,.T.);
#737=ADVANCED_FACE('F554',(#736),#711,.F.);
#738=CARTESIAN_POINT('',(9.625,-22.5,9.));
#739=DIRECTION('',(0.,1.,0.));
#740=DIRECTION('',(0.,0.,1.));
#741=AXIS2_PLACEMENT_3D('',#738,#739,#740);
#742=PLANE('',#741);
#743=DIRECTION('',(1.,0.,0.));
#744=VECTOR('',#743,1.);
#745=CARTESIAN_POINT('',(9.625,-22.5,-9.));
#746=LINE('',#745,#744);
#747=CARTESIAN_POINT('',(9.625,-22.5,-9.));
#748=VERTEX_POINT('',#747);
#749=EDGE_CURVE('E317',#717,#748,#746,.T.);
#750=ORIENTED_EDGE('',*,*,#749,.T.);
#751=DIRECTION('',(0.,0.,-1.));
#752=VECTOR('',#751,1.);
#753=CARTESIAN_POINT('',(9.625,-22.5,9.));
#754=LINE('',#753,#752);
#755=CARTESIAN_POINT('',(9.625,-22.5,9.));
#756=VERTEX_POINT('',#755);
#757=EDGE_CURVE('E405',#756,#748,#754,.T.);
#758=ORIENTED_EDGE('',*,*,#757,.F.);
#759=DIRECTION('',(1.,0.,0.));
#760=VECTOR('',#759,1.);
#761=CARTESIAN_POINT('',(9.625,-22.5,9.));
#762=LINE('',#761,#760);
#763=EDGE_CURVE('E371',#725,#756,#762,.T.);
#764=ORIENTED_EDGE('',*,*,#763,.F.);
#765=ORIENTED_EDGE('',*,*,#726,.T.);
#766=EDGE_LOOP('',(#750,#758,#764,#765));
#767=FACE_BOUND('',#766,.T.);
#768=ADVANCED_FACE('F550',(#767),#742,.F.);
#769=CARTESIAN_POINT('',(9.625,-25.,9.));
#770=DIRECTION('',(1.,0.,0.));
#771=DIRECTION('',(0.,0.,-1.));
#772=AXIS2_PLACEMENT_3D('',#769,#770,#771);
#773=PLANE('',#772);
#774=DIRECTION('',(0.,-1.,0.));
#775=VECTOR('',#774,1.);
#776=CARTESIAN_POINT('',(9.625,-25.,-9.));
#777=LINE('',#776,#775);
#778=CARTESIAN_POINT('',(9.625,-25.,-9.));
#779=VERTEX_POINT('',#778);
#780=EDGE_CURVE('E319',#748,#779,#777,.T.);
#781=ORIENTED_EDGE('',*,*,#780,.T.);
#782=DIRECTION('',(0.,0.,-1.));
#783=VECTOR('',#782,1.);
#784=CARTESIAN_POINT('',(9.625,-25.,9.));
#785=LINE('',#784,#783);
#786=CARTESIAN_POINT('',(9.625,-25.,9.));
#787=VERTEX_POINT('',#786);
#788=EDGE_CURVE('E402',#787,#779,#785,.T.);
#789=ORIENTED_EDGE('',*,*,#788,.F.);
#790=DIRECTION('',(0.,-1.,0.));
#791=VECTOR('',#790,1.);
#792=CARTESIAN_POINT('',(9.625,-25.,9.));
#793=LINE('',#792,#791);
#794=EDGE_CURVE('E373',#756,#787,#793,.T.);
#795=ORIENTED_EDGE('',*,*,#794,.F.);
#796=ORIENTED_EDGE('',*,*,#757,.T.);
#797=EDGE_LOOP('',(#781,#789,#795,#796));
#798=FACE_BOUND('',#797,.T.);
#799=ADVANCED_FACE('F546',(#798),#773,.F.);
#800=CARTESIAN_POINT('',(12.5625,-25.,9.));
#801=DIRECTION('',(0.,1.,0.));
#802=DIRECTION('',(0.,0.,1.));
#803=AXIS2_PLACEMENT_3D('',#800,#801,#802);
#804=PLANE('',#803);
#805=DIRECTION('',(1.,0.,0.));
#806=VECTOR('',#805,1.);
#807=CARTESIAN_POINT('',(12.5625,-25.,-9.));
#808=LINE('',#807,#806);
#809=CARTESIAN_POINT('',(12.5625,-25.,-9.));
#810=VERTEX_POINT('',#809);
#811=EDGE_CURVE('E321',#779,#810,#808,.T.);
#812=ORIENTED_EDGE('',*,*,#811,.T.);
#813=DIRECTION('',(0.,0.,-1.));
#814=VECTOR('',#813,1.);
#815=CARTESIAN_POINT('',(12.5625,-25.,9.));
#816=LINE('',#815,#814);
#817=CARTESIAN_POINT('',(12.5625,-25.,9.));
#818=VERTEX_POINT('',#817);
#819=EDGE_CURVE('E399',#818,#810,#816,.T.);
#820=ORIENTED_EDGE('',*,*,#819,.F.);
#821=DIRECTION('',(1.,0.,0.));
#822=VECTOR('',#821,1.);
#823=CARTESIAN_POINT('',(12.5625,-25.,9.));
#824=LINE('',#823,#822);
#825=EDGE_CURVE('E375',#787,#818,#824,.T.);
#826=ORIENTED_EDGE('',*,*,#825,.F.);
#827=ORIENTED_EDGE('',*,*,#788,.T.);
#828=EDGE_LOOP('',(#812,#820,#826,#827));
#829=FACE_BOUND('',#828,.T.);
#830=ADVANCED_FACE('F542',(#829),#804,.F.);
#831=CARTESIAN_POINT('',(12.5625,-27.5,9.));
#832=DIRECTION('',(1.,0.,0.));
#833=DIRECTION('',(0.,0.,-1.));
#834=AXIS2_PLACEMENT_3D('',#831,#832,#833);
#835=PLANE('',#834);
#836=DIRECTION('',(0.,-1.,0.));
#837=VECTOR('',#836,1.);
#838=CARTESIAN_POINT('',(12.5625,-27.5,-9.));
#839=LINE('',#838,#837);
#840=CARTESIAN_POINT('',(12.5625,-27.5,-9.));
#841=VERTEX_POINT('',#840);
#842=EDGE_CURVE('E323',#810,#841,#839,.T.);
#843=ORIENTED_EDGE('',*,*,#842,.T.);
#844=DIRECTION('',(0.,0.,-1.));
#845=VECTOR('',#844,1.);
#846=CARTESIAN_POINT('',(12.5625,-27.5,9.));
#847=LINE('',#846,#845);
#848=CARTESIAN_POINT('',(12.5625,-27.5,9.));
#849=VERTEX_POINT('',#848);
#850=EDGE_CURVE('E396',#849,#841,#847,.T.);
#851=ORIENTED_EDGE('',*,*,#850,.F.);
#852=DIRECTION('',(0.,-1.,0.));
#853=VECTOR('',#852,1.);
#854=CARTESIAN_POINT('',(12.5625,-27.5,9.));
#855=LINE('',#854,#853);
#856=EDGE_CURVE('E377',#818,#849,#855,.T.);
#857=ORIENTED_EDGE('',*,*,#856,.F.);
#858=ORIENTED_EDGE('',*,*,#819,.T.);
#859=EDGE_LOOP('',(#843,#851,#857,#858));
#860=FACE_BOUND('',#859,.T.);
#861=ADVANCED_FACE('F538',(#860),#835,.F.);
#862=CARTESIAN_POINT('',(15.5,-27.5,9.));
#863=DIRECTION('',(0.,1.,0.));
#864=DIRECTION('',(0.,0.,1.));
#865=AXIS2_PLACEMENT_3D('',#862,#863,#864);
#866=PLANE('',#865);
#867=DIRECTION('',(1.,0.,0.));
#868=VECTOR('',#867,1.);
#869=CARTESIAN_POINT('',(15.5,-27.5,-9.));
#870=LINE('',#869,#868);
#871=CARTESIAN_POINT('',(15.5,-27.5,-9.));
#872=VERTEX_POINT('',#871);
#873=EDGE_CURVE('E325',#841,#872,#870,.T.);
#874=ORIENTED_EDGE('',*,*,#873,.T.);
#875=DIRECTION('',(0.,0.,-1.));
#876=VECTOR('',#875,1.);
#877=CARTESIAN_POINT('',(15.5,-27.5,9.));
#878=LINE('',#877,#876);
#879=CARTESIAN_POINT('',(15.5,-27.5,9.));
#880=VERTEX_POINT('',#879);
#881=EDGE_CURVE('E393',#880,#872,#878,.T.);
#882=ORIENTED_EDGE('',*,*,#881,.F.);
#883=DIRECTION('',(1.,0.,0.));
#884=VECTOR('',#883,1.);
#885=CARTESIAN_POINT('',(15.5,-27.5,9.));
#886=LINE('',#885,#884);
#887=EDGE_CURVE('E379',#849,#880,#886,.T.);
#888=ORIENTED_EDGE('',*,*,#887,.F.);
#889=ORIENTED_EDGE('',*,*,#850,.T.);
#890=EDGE_LOOP('',(#874,#882,#888,#889));
#891=FACE_BOUND('',#890,.T.);
#892=ADVANCED_FACE('F534',(#891),#866,.F.);
#893=CARTESIAN_POINT('',(15.5,-30.,9.));
#894=DIRECTION('',(1.,0.,0.));
#895=DIRECTION('',(0.,0.,-1.));
#896=AXIS2_PLACEMENT_3D('',#893,#894,#895);
#897=PLANE('',#896);
#898=DIRECTION('',(0.,-1.,0.));
#899=VECTOR('',#898,1.);
#900=CARTESIAN_POINT('',(15.5,-30.,-9.));
#901=LINE('',#900,#899);
#902=CARTESIAN_POINT('',(15.5,-30.,-9.));
#903=VERTEX_POINT('',#902);
#904=EDGE_CURVE('E327',#872,#903,#901,.T.);
#905=ORIENTED_EDGE('',*,*,#904,.T.);
#906=DIRECTION('',(0.,0.,-1.));
#907=VECTOR('',#906,1.);
#908=CARTESIAN_POINT('',(15.5,-30.,9.));
#909=LINE('',#908,#907);
#910=CARTESIAN_POINT('',(15.5,-30.,9.));
#911=VERTEX_POINT('',#910);
#912=EDGE_CURVE('E390',#911,#903,#909,.T.);
#913=ORIENTED_EDGE('',*,*,#912,.F.);
#914=DIRECTION('',(0.,-1.,0.));
#915=VECTOR('',#914,1.);
#916=CARTESIAN_POINT('',(15.5,-30.,9.));
#917=LINE('',#916,#915);
#918=EDGE_CURVE('E381',#880,#911,#917,.T.);
#919=ORIENTED_EDGE('',*,*,#918,.F.);
#920=ORIENTED_EDGE('',*,*,#881,.T.);
#921=EDGE_LOOP('',(#905,#913,#919,#920));
#922=FACE_BOUND('',#921,.T.);
#923=ADVANCED_FACE('F530',(#922),#897,.F.);
#924=CARTESIAN_POINT('',(15.5,-30.,9.));
#925=DIRECTION('',(0.,1.,0.));
#926=DIRECTION('',(0.,0.,1.));
#927=AXIS2_PLACEMENT_3D('',#924,#925,#926);
#928=PLANE('',#927);
#929=DIRECTION('',(1.,0.,0.));
#930=VECTOR('',#929,1.);
#931=CARTESIAN_POINT('',(15.5,-30.,-9.));
#932=LINE('',#931,#930);
#933=CARTESIAN_POINT('',(19.,-30.,-9.));
#934=VERTEX_POINT('',#933);
#935=EDGE_CURVE('E329',#903,#934,#932,.T.);
#936=ORIENTED_EDGE('',*,*,#935,.T.);
#937=DIRECTION('',(0.,0.,-1.));
#938=VECTOR('',#937,1.);
#939=CARTESIAN_POINT('',(19.,-30.,9.));
#940=LINE('',#939,#938);
#941=CARTESIAN_POINT('',(19.,-30.,9.));
#942=VERTEX_POINT('',#941);
#943=EDGE_CURVE('E387',#942,#934,#940,.T.);
#944=ORIENTED_EDGE('',*,*,#943,.F.);
#945=DIRECTION('',(1.,0.,0.));
#946=VECTOR('',#945,1.);
#947=CARTESIAN_POINT('',(15.5,-30.,9.));
#948=LINE('',#947,#946);
#949=EDGE_CURVE('E383',#911,#942,#948,.T.);
#950=ORIENTED_EDGE('',*,*,#949,.F.);
#951=ORIENTED_EDGE('',*,*,#912,.T.);
#952=EDGE_LOOP('',(#936,#944,#950,#951));
#953=FACE_BOUND('',#952,.T.);
#954=ADVANCED_FACE('F525',(#953),#928,.F.);
#955=CARTESIAN_POINT('',(19.,30.,9.));
#956=DIRECTION('',(-1.,0.,0.));
#957=DIRECTION('',(0.,-1.,0.));
#958=AXIS2_PLACEMENT_3D('',#955,#956,#957);
#959=PLANE('',#958);
#960=CARTESIAN_POINT('',(19.,23.,0.));
#961=DIRECTION('',(1.,0.,0.));
#962=DIRECTION('',(0.,1.,0.));
#963=AXIS2_PLACEMENT_3D('',#960,#961,#962);
#964=CIRCLE('',#963,3.);
#965=CARTESIAN_POINT('',(19.,26.,0.));
#966=VERTEX_POINT('',#965);
#967=EDGE_CURVE('E267',#966,#966,#964,.T.);
#968=ORIENTED_EDGE('',*,*,#967,.F.);
#969=EDGE_LOOP('',(#968));
#970=FACE_BOUND('',#969,.T.);
#971=DIRECTION('',(0.,1.,0.));
#972=VECTOR('',#971,1.);
#973=CARTESIAN_POINT('',(19.,30.,-9.));
#974=LINE('',#973,#972);
#975=CARTESIAN_POINT('',(19.,28.,-9.));
#976=VERTEX_POINT('',#975);
#977=EDGE_CURVE('E331',#934,#976,#974,.T.);
#978=ORIENTED_EDGE('',*,*,#977,.T.);
#979=DIRECTION('',(0.,0.,1.));
#980=VECTOR('',#979,1.);
#981=CARTESIAN_POINT('',(19.,28.,9.));
#982=LINE('',#981,#980);
#983=CARTESIAN_POINT('',(19.,28.,9.));
#984=VERTEX_POINT('',#983);
#985=EDGE_CURVE('E34',#976,#984,#982,.T.);
#986=ORIENTED_EDGE('',*,*,#985,.T.);
#987=DIRECTION('',(0.,1.,0.));
#988=VECTOR('',#987,1.);
#989=CARTESIAN_POINT('',(19.,30.,9.));
#990=LINE('',#989,#988);
#991=EDGE_CURVE('E385',#942,#984,#990,.T.);
#992=ORIENTED_EDGE('',*,*,#991,.F.);
#993=ORIENTED_EDGE('',*,*,#943,.T.);
#994=EDGE_LOOP('',(#978,#986,#992,#993));
#995=FACE_BOUND('',#994,.T.);
#996=ADVANCED_FACE('F517',(#970,#995),#959,.F.);
#997=CARTESIAN_POINT('',(-19.,30.,9.));
#998=DIRECTION('',(0.,-1.,0.));
#999=DIRECTION('',(0.,0.,-1.));
#1000=AXIS2_PLACEMENT_3D('',#997,#998,#999);
#1001=PLANE('',#1000);
#1002=DIRECTION('',(-1.,0.,0.));
#1003=VECTOR('',#1002,1.);
#1004=CARTESIAN_POINT('',(-19.,30.,-7.));
#1005=LINE('',#1004,#1003);
#1006=CARTESIAN_POINT('',(17.,30.,-7.));
#1007=VERTEX_POINT('',#1006);
#1008=CARTESIAN_POINT('',(-17.,30.,-7.));
#1009=VERTEX_POINT('',#1008);
#1010=EDGE_CURVE('E479',#1007,#1009,#1005,.T.);
#1011=ORIENTED_EDGE('',*,*,#1010,.T.);
#1012=DIRECTION('',(0.,0.,1.));
#1013=VECTOR('',#1012,1.);
#1014=CARTESIAN_POINT('',(-17.,30.,9.));
#1015=LINE('',#1014,#1013);
#1016=CARTESIAN_POINT('',(-17.,30.,6.99999999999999));
#1017=VERTEX_POINT('',#1016);
#1018=EDGE_CURVE('E481',#1009,#1017,#1015,.T.);
#1019=ORIENTED_EDGE('',*,*,#1018,.T.);
#1020=DIRECTION('',(1.,0.,0.));
#1021=VECTOR('',#1020,1.);
#1022=CARTESIAN_POINT('',(19.,30.,6.99999999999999));
#1023=LINE('',#1022,#1021);
#1024=CARTESIAN_POINT('',(17.,30.,6.99999999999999));
#1025=VERTEX_POINT('',#1024);
#1026=EDGE_CURVE('E475',#1017,#1025,#1023,.T.);
#1027=ORIENTED_EDGE('',*,*,#1026,.T.);
#1028=DIRECTION('',(0.,0.,-1.));
#1029=VECTOR('',#1028,1.);
#1030=CARTESIAN_POINT('',(17.,30.,9.));
#1031=LINE('',#1030,#1029);
#1032=EDGE_CURVE('E477',#1025,#1007,#1031,.T.);
#1033=ORIENTED_EDGE('',*,*,#1032,.T.);
#1034=EDGE_LOOP('',(#1011,#1019,#1027,#1033));
#1035=FACE_BOUND('',#1034,.T.);
#1036=CARTESIAN_POINT('',(0.,30.,0.));
#1037=DIRECTION('',(0.,-1.,0.));
#1038=DIRECTION('',(0.,0.,-1.));
#1039=AXIS2_PLACEMENT_3D('',#1036,#1037,#1038);
#1040=CIRCLE('',#1039,6.);
#1041=CARTESIAN_POINT('',(0.,30.,-6.));
#1042=VERTEX_POINT('',#1041);
#1043=EDGE_CURVE('E277',#1042,#1042,#1040,.T.);
#1044=ORIENTED_EDGE('',*,*,#1043,.T.);
#1045=EDGE_LOOP('',(#1044));
#1046=FACE_BOUND('',#1045,.T.);
#1047=ADVANCED_FACE('F486',(#1035,#1046),#1001,.F.);
#1048=CARTESIAN_POINT('',(-19.,-30.,9.));
#1049=DIRECTION('',(0.,0.,1.));
#1050=DIRECTION('',(1.,0.,0.));
#1051=AXIS2_PLACEMENT_3D('',#1048,#1049,#1050);
#1052=PLANE('',#1051);
#1053=ORIENTED_EDGE('',*,*,#991,.T.);
#1054=DIRECTION('',(-1.,0.,0.));
#1055=VECTOR('',#1054,1.);
#1056=CARTESIAN_POINT('',(-19.,28.,9.));
#1057=LINE('',#1056,#1055);
#1058=EDGE_CURVE('E11',#984,#150,#1057,.T.);
#1059=ORIENTED_EDGE('',*,*,#1058,.T.);
#1060=ORIENTED_EDGE('',*,*,#153,.T.);
#1061=ORIENTED_EDGE('',*,*,#205,.T.);
#1062=ORIENTED_EDGE('',*,*,#236,.T.);
#1063=ORIENTED_EDGE('',*,*,#267,.T.);
#1064=ORIENTED_EDGE('',*,*,#298,.T.);
#1065=ORIENTED_EDGE('',*,*,#329,.T.);
#1066=ORIENTED_EDGE('',*,*,#360,.T.);
#1067=ORIENTED_EDGE('',*,*,#391,.T.);
#1068=ORIENTED_EDGE('',*,*,#422,.T.);
#1069=ORIENTED_EDGE('',*,*,#453,.T.);
#1070=ORIENTED_EDGE('',*,*,#484,.T.);
#1071=ORIENTED_EDGE('',*,*,#515,.T.);
#1072=ORIENTED_EDGE('',*,*,#546,.T.);
#1073=ORIENTED_EDGE('',*,*,#577,.T.);
#1074=ORIENTED_EDGE('',*,*,#608,.T.);
#1075=ORIENTED_EDGE('',*,*,#639,.T.);
#1076=ORIENTED_EDGE('',*,*,#670,.T.);
#1077=ORIENTED_EDGE('',*,*,#701,.T.);
#1078=ORIENTED_EDGE('',*,*,#732,.T.);
#1079=ORIENTED_EDGE('',*,*,#763,.T.);
#1080=ORIENTED_EDGE('',*,*,#794,.T.);
#1081=ORIENTED_EDGE('',*,*,#825,.T.);
#1082=ORIENTED_EDGE('',*,*,#856,.T.);
#1083=ORIENTED_EDGE('',*,*,#887,.T.);
#1084=ORIENTED_EDGE('',*,*,#918,.T.);
#1085=ORIENTED_EDGE('',*,*,#949,.T.);
#1086=EDGE_LOOP('',(#1053,#1059,#1060,#1061,#1062,#1063,#1064,#1065,#1066,#1067,#1068,#1069,
#1070,#1071,#1072,#1073,#1074,#1075,#1076,#1077,#1078,#1079,#1080,#1081,#1082,#1083,#1084,#1085));
#1087=FACE_BOUND('',#1086,.T.);
#1088=ADVANCED_FACE('F260',(#1087),#1052,.T.);
#1089=CARTESIAN_POINT('',(-19.,-30.,-9.));
#1090=DIRECTION('',(0.,0.,1.));
#1091=DIRECTION('',(1.,0.,0.));
#1092=AXIS2_PLACEMENT_3D('',#1089,#1090,#1091);
#1093=PLANE('',#1092);
#1094=ORIENTED_EDGE('',*,*,#169,.F.);
#1095=DIRECTION('',(1.,0.,0.));
#1096=VECTOR('',#1095,1.);
#1097=CARTESIAN_POINT('',(-19.,28.,-9.));
#1098=LINE('',#1097,#1096);
#1099=EDGE_CURVE('E48',#160,#976,#1098,.T.);
#1100=ORIENTED_EDGE('',*,*,#1099,.T.);
#1101=ORIENTED_EDGE('',*,*,#977,.F.);
#1102=ORIENTED_EDGE('',*,*,#935,.F.);
#1103=ORIENTED_EDGE('',*,*,#904,.F.);
#1104=ORIENTED_EDGE('',*,*,#873,.F.);
#1105=ORIENTED_EDGE('',*,*,#842,.F.);
#1106=ORIENTED_EDGE('',*,*,#811,.F.);
#1107=ORIENTED_EDGE('',*,*,#780,.F.);
#1108=ORIENTED_EDGE('',*,*,#749,.F.);
#1109=ORIENTED_EDGE('',*,*,#718,.F.);
#1110=ORIENTED_EDGE('',*,*,#687,.F.);
#1111=ORIENTED_EDGE('',*,*,#656,.F.);
#1112=ORIENTED_EDGE('',*,*,#625,.F.);
#1113=ORIENTED_EDGE('',*,*,#594,.F.);
#1114=ORIENTED_EDGE('',*,*,#563,.F.);
#1115=ORIENTED_EDGE('',*,*,#532,.F.);
#1116=ORIENTED_EDGE('',*,*,#501,.F.);
#1117=ORIENTED_EDGE('',*,*,#470,.F.);
#1118=ORIENTED_EDGE('',*,*,#439,.F.);
#1119=ORIENTED_EDGE('',*,*,#408,.F.);
#1120=ORIENTED_EDGE('',*,*,#377,.F.);
#1121=ORIENTED_EDGE('',*,*,#346,.F.);
#1122=ORIENTED_EDGE('',*,*,#315,.F.);
#1123=ORIENTED_EDGE('',*,*,#284,.F.);
#1124=ORIENTED_EDGE('',*,*,#253,.F.);
#1125=ORIENTED_EDGE('',*,*,#222,.F.);
#1126=ORIENTED_EDGE('',*,*,#191,.F.);
#1127=EDGE_LOOP('',(#1094,#1100,#1101,#1102,#1103,#1104,#1105,#1106,#1107,#1108,#1109,#1110,
#1111,#1112,#1113,#1114,#1115,#1116,#1117,#1118,#1119,#1120,#1121,#1122,#1123,#1124,#1125,#1126));
#1128=FACE_BOUND('',#1127,.T.);
#1129=ADVANCED_FACE('F255',(#1128),#1093,.F.);
#1130=CARTESIAN_POINT('',(6.,26.,0.));
#1131=CARTESIAN_POINT('',(5.99999934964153,25.9999991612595,-0.0788941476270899));
#1132=CARTESIAN_POINT('',(5.99843869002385,25.9968820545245,-0.15779662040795));
#1133=CARTESIAN_POINT('',(5.99224358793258,25.98446072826,-0.315001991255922));
#1134=CARTESIAN_POINT('',(5.98760776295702,25.9751537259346,-0.393304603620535));
#1135=CARTESIAN_POINT('',(5.96921978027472,25.9380421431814,-0.626628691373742));
#1136=CARTESIAN_POINT('',(5.95098734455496,25.9010471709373,-0.779952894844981));
#1137=CARTESIAN_POINT('',(5.90448966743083,25.8044182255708,-1.07683586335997));
#1138=CARTESIAN_POINT('',(5.87626344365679,25.7448722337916,-1.22043005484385));
#1139=CARTESIAN_POINT('',(5.81237302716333,25.6052887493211,-1.49540820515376));
#1140=CARTESIAN_POINT('',(5.77670942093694,25.5252528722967,-1.62679312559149));
#1141=CARTESIAN_POINT('',(5.69868752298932,25.3414460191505,-1.88252701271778));
#1142=CARTESIAN_POINT('',(5.65605474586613,25.2365320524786,-2.0059694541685));
#1143=CARTESIAN_POINT('',(5.56980033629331,25.0084440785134,-2.23433451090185));
#1144=CARTESIAN_POINT('',(5.5261779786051,24.8852562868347,-2.33924301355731));
#1145=CARTESIAN_POINT('',(5.43896347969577,24.6125156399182,-2.53576864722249));
#1146=CARTESIAN_POINT('',(5.39563602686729,24.4616590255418,-2.62572411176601));
#1147=CARTESIAN_POINT('',(5.33782449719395,24.2240491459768,-2.7403403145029));
#1148=CARTESIAN_POINT('',(5.31974570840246,24.1429290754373,-2.77516786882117));
#1149=CARTESIAN_POINT('',(5.28665768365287,23.9773994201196,-2.83769299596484));
#1150=CARTESIAN_POINT('',(5.27164663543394,23.8929918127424,-2.86539478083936));
#1151=CARTESIAN_POINT('',(5.24610341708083,23.7266042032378,-2.91188280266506));
#1152=CARTESIAN_POINT('',(5.23535838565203,23.6447772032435,-2.93110042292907));
#1153=CARTESIAN_POINT('',(5.21757784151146,23.4794450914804,-2.9626355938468));
#1154=CARTESIAN_POINT('',(5.21054036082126,23.3959408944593,-2.97495680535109));
#1155=CARTESIAN_POINT('',(5.20047756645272,23.2279936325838,-2.99251382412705));
#1156=CARTESIAN_POINT('',(5.19744983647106,23.1435511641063,-2.99775389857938));
#1157=CARTESIAN_POINT('',(5.19552555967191,22.9745063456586,-3.00108452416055));
#1158=CARTESIAN_POINT('',(5.19662861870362,22.8899040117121,-2.99917575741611));
#1159=CARTESIAN_POINT('',(5.20534668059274,22.6572461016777,-2.98404973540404));
#1160=CARTESIAN_POINT('',(5.21726794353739,22.5097558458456,-2.96335042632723));
#1161=CARTESIAN_POINT('',(5.25228182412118,22.2208063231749,-2.90082280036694));
#1162=CARTESIAN_POINT('',(5.2753780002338,22.0793489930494,-2.85898775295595));
#1163=CARTESIAN_POINT('',(5.33062568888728,21.8023203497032,-2.75462843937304));
#1164=CARTESIAN_POINT('',(5.36297559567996,21.6669628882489,-2.69164495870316));
#1165=CARTESIAN_POINT('',(5.43310175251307,21.408095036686,-2.54712530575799));
#1166=CARTESIAN_POINT('',(5.47088043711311,21.2845900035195,-2.46558080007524));
#1167=CARTESIAN_POINT('',(5.55339485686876,21.0364369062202,-2.27419808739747));
#1168=CARTESIAN_POINT('',(5.59840533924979,20.9136295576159,-2.16208335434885));
#1169=CARTESIAN_POINT('',(5.6864286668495,20.6877935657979,-1.91866675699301));
#1170=CARTESIAN_POINT('',(5.72944054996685,20.5847743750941,-1.78735577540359));
#1171=CARTESIAN_POINT('',(5.81105962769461,20.3969430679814,-1.50154951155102));
#1172=CARTESIAN_POINT('',(5.84936952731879,20.3131985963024,-1.3462607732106));
#1173=CARTESIAN_POINT('',(5.91473643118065,20.1737088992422,-1.02139864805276));
#1174=CARTESIAN_POINT('',(5.94180236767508,20.1179414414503,-0.851836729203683));
#1175=CARTESIAN_POINT('',(5.97973001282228,20.0405737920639,-0.518299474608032));
#1176=CARTESIAN_POINT('',(5.99174814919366,20.0165262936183,-0.355024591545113));
#1177=CARTESIAN_POINT('',(6.00219040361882,19.9956058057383,-0.0263387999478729));
#1178=CARTESIAN_POINT('',(6.00062096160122,19.9987199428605,0.139071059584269));
#1179=CARTESIAN_POINT('',(5.98473576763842,20.0306200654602,0.453698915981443));
#1180=CARTESIAN_POINT('',(5.97141737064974,20.0573975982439,0.603178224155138));
#1181=CARTESIAN_POINT('',(5.93466513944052,20.1327142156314,0.895220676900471));
#1182=CARTESIAN_POINT('',(5.91123019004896,20.1812556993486,1.03778305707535));
#1183=CARTESIAN_POINT('',(5.85552754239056,20.2999953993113,1.31666582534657));
#1184=CARTESIAN_POINT('',(5.82302645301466,20.3707731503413,1.45269119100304));
#1185=CARTESIAN_POINT('',(5.75231922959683,20.5313226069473,1.71138408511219));
#1186=CARTESIAN_POINT('',(5.71411066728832,20.6211024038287,1.83404588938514));
#1187=CARTESIAN_POINT('',(5.63124663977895,20.8272812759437,2.07530306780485));
#1188=CARTESIAN_POINT('',(5.58632654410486,20.9454286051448,2.19231623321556));
#1189=CARTESIAN_POINT('',(5.49787174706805,21.1997754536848,2.40556896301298));
#1190=CARTESIAN_POINT('',(5.4543380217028,21.3359873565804,2.50179415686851));
#1191=CARTESIAN_POINT('',(5.3715357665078,21.6309309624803,2.675123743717));
#1192=CARTESIAN_POINT('',(5.33257588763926,21.7904337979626,2.75107648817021));
#1193=CARTESIAN_POINT('',(5.26722216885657,22.1225302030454,2.87424847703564));
#1194=CARTESIAN_POINT('',(5.24081214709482,22.2951065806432,2.92150474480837));
#1195=CARTESIAN_POINT('',(5.2068450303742,22.6307306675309,2.98158506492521));
#1196=CARTESIAN_POINT('',(5.19772150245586,22.7931027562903,2.997278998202));
#1197=CARTESIAN_POINT('',(5.19496064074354,23.1183412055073,3.00206745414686));
#1198=CARTESIAN_POINT('',(5.20131659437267,23.2812073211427,2.99117350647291));
#1199=CARTESIAN_POINT('',(5.22713585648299,23.5864504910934,2.94577840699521));
#1200=CARTESIAN_POINT('',(5.24529281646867,23.7293013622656,2.91362505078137));
#1201=CARTESIAN_POINT('',(5.29113050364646,24.0074244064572,2.82952596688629));
#1202=CARTESIAN_POINT('',(5.3188142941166,24.1426941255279,2.77757387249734));
#1203=CARTESIAN_POINT('',(5.38285583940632,24.4118743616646,2.65144766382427));
#1204=CARTESIAN_POINT('',(5.41967139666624,24.5450829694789,2.57601505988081));
#1205=CARTESIAN_POINT('',(5.49706022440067,24.7978243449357,2.40645126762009));
#1206=CARTESIAN_POINT('',(5.53763544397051,24.9173499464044,2.31231035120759));
#1207=CARTESIAN_POINT('',(5.62386853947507,25.1544228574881,2.094616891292));
#1208=CARTESIAN_POINT('',(5.66954494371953,25.2699651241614,1.96888052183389));
#1209=CARTESIAN_POINT('',(5.75633712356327,25.478801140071,1.69843715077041));
#1210=CARTESIAN_POINT('',(5.79745043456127,25.5720828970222,1.55371998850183));
#1211=CARTESIAN_POINT('',(5.85251406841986,25.6931781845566,1.32452333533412));
#1212=CARTESIAN_POINT('',(5.86982524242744,25.7305202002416,1.24575314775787));
#1213=CARTESIAN_POINT('',(5.90168845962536,25.7983616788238,1.08479725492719));
#1214=CARTESIAN_POINT('',(5.91624185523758,25.8288644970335,1.00261324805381));
#1215=CARTESIAN_POINT('',(5.94212690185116,25.8826072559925,0.835616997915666));
#1216=CARTESIAN_POINT('',(5.95346557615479,25.905863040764,0.750810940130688));
#1217=CARTESIAN_POINT('',(5.97260771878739,25.9448825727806,0.579142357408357));
#1218=CARTESIAN_POINT('',(5.98041334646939,25.9606508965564,0.49228112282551));
#1219=CARTESIAN_POINT('',(5.99085829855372,25.9816846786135,0.337824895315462));
#1220=CARTESIAN_POINT('',(5.99428035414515,25.988546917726,0.270495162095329));
#1221=CARTESIAN_POINT('',(5.99885151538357,25.997705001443,0.135445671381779));
#1222=CARTESIAN_POINT('',(6.00000055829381,26.0000007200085,0.0677259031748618));
#1223=CARTESIAN_POINT('',(6.,26.,0.));
#1224=B_SPLINE_CURVE_WITH_KNOTS('',3,(#1130,#1131,#1132,#1133,#1134,#1135,#1136,#1137,#1138,
#1139,#1140,#1141,#1142,#1143,#1144,#1145,#1146,#1147,#1148,#1149,#1150,#1151,#1152,#1153,#1154,
#1155,#1156,#1157,#1158,#1159,#1160,#1161,#1162,#1163,#1164,#1165,#1166,#1167,#1168,#1169,#1170,
#1171,#1172,#1173,#1174,#1175,#1176,#1177,#1178,#1179,#1180,#1181,#1182,#1183,#1184,#1185,#1186,
#1187,#1188,#1189,#1190,#1191,#1192,#1193,#1194,#1195,#1196,#1197,#1198,#1199,#1200,#1201,#1202,
#1203,#1204,#1205,#1206,#1207,#1208,#1209,#1210,#1211,#1212,#1213,#1214,#1215,#1216,#1217,#1218,
#1219,#1220,#1221,#1222,#1223),.UNSPECIFIED.,.T.,.F.,(4,2,2,2,2,2,2,2,2,2,2,2,2,2,2,2,2,2,2,2,2,
2,2,2,2,2,2,2,2,2,2,2,2,2,2,2,2,2,2,2,2,2,2,2,2,2,4),(0.,0.236611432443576,0.473329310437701,
0.947100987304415,1.41904300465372,1.89094781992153,2.39140181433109,2.89223525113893,
3.4319083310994,3.70192714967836,3.97178599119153,4.22563720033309,4.47935352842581,
4.73291689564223,4.98645606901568,5.4323867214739,5.87845946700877,6.33492255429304,
6.79159098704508,7.30616358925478,7.82098138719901,8.35970601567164,8.89800185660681,
9.39171406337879,9.8851922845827,10.3404225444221,10.7957029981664,11.2640010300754,
11.7324988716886,12.2470036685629,12.7618630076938,13.3016558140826,13.8407507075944,
14.3280945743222,14.8152271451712,15.2559532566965,15.6968212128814,16.1673090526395,
16.6380421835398,17.1659726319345,17.6941868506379,17.9605054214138,18.2266930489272,
18.4922945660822,18.7577335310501,18.9608446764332,19.1639614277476),.UNSPECIFIED.);
#1225=CARTESIAN_POINT('',(6.,26.,0.));
#1226=VERTEX_POINT('',#1225);
#1227=EDGE_CURVE('E264',#1226,#1226,#1224,.T.);
#1228=ORIENTED_EDGE('',*,*,#1227,.T.);
#1229=EDGE_LOOP('',(#1228));
#1230=FACE_BOUND('',#1229,.T.);
#1231=ORIENTED_EDGE('',*,*,#967,.T.);
#1232=EDGE_LOOP('',(#1231));
#1233=FACE_BOUND('',#1232,.T.);
#1234=ADVANCED_FACE('F238',(#1230,#1233),#23,.F.);
#1235=CARTESIAN_POINT('',(0.,0.,0.));
#1236=DIRECTION('',(0.,-1.,0.));
#1237=DIRECTION('',(0.,0.,-1.));
#1238=AXIS2_PLACEMENT_3D('',#1235,#1236,#1237);
#1239=CYLINDRICAL_SURFACE('',#1238,6.);
#1240=ORIENTED_EDGE('',*,*,#1227,.F.);
#1241=EDGE_LOOP('',(#1240));
#1242=FACE_BOUND('',#1241,.T.);
#1243=ORIENTED_EDGE('',*,*,#1043,.F.);
#1244=EDGE_LOOP('',(#1243));
#1245=FACE_BOUND('',#1244,.T.);
#1246=CARTESIAN_POINT('',(0.,9.99999999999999,0.));
#1247=DIRECTION('',(0.,-1.,0.));
#1248=DIRECTION('',(0.,0.,-1.));
#1249=AXIS2_PLACEMENT_3D('',#1246,#1247,#1248);
#1250=CIRCLE('',#1249,6.);
#1251=CARTESIAN_POINT('',(0.,9.99999999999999,-6.));
#1252=VERTEX_POINT('',#1251);
#1253=EDGE_CURVE('E508',#1252,#1252,#1250,.T.);
#1254=ORIENTED_EDGE('',*,*,#1253,.T.);
#1255=EDGE_LOOP('',(#1254));
#1256=FACE_BOUND('',#1255,.T.);
#1257=ORIENTED_EDGE('',*,*,#121,.F.);
#1258=EDGE_LOOP('',(#1257));
#1259=FACE_BOUND('',#1258,.T.);
#1260=ADVANCED_FACE('F228',(#1242,#1245,#1256,#1259),#1239,.F.);
#1261=CARTESIAN_POINT('',(0.,6.5358983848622,0.));
#1262=DIRECTION('',(0.,1.,0.));
#1263=DIRECTION('',(0.,0.,1.));
#1264=AXIS2_PLACEMENT_3D('',#1261,#1262,#1263);
#1265=CONICAL_SURFACE('',#1264,0.,1.04719755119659);
#1266=ORIENTED_EDGE('',*,*,#1253,.F.);
#1267=EDGE_LOOP('',(#1266));
#1268=FACE_BOUND('',#1267,.T.);
#1269=CARTESIAN_POINT('',(0.,6.5358983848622,0.));
#1270=VERTEX_POINT('',#1269);
#1271=VERTEX_LOOP('',#1270);
#1272=FACE_BOUND('',#1271,.T.);
#1273=ADVANCED_FACE('F225',(#1268,#1272),#1265,.F.);
#1274=CARTESIAN_POINT('',(17.,30.,9.));
#1275=DIRECTION('',(-0.707106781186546,-0.707106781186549,0.));
#1276=DIRECTION('',(0.707106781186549,-0.707106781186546,0.));
#1277=AXIS2_PLACEMENT_3D('',#1274,#1275,#1276);
#1278=PLANE('',#1277);
#1279=DIRECTION('',(-0.577350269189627,0.577350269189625,0.577350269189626));
#1280=VECTOR('',#1279,1.);
#1281=CARTESIAN_POINT('',(11.6666666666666,35.3333333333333,-1.66666666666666));
#1282=LINE('',#1281,#1280);
#1283=EDGE_CURVE('E502',#1007,#976,#1282,.F.);
#1284=ORIENTED_EDGE('',*,*,#1283,.F.);
#1285=ORIENTED_EDGE('',*,*,#1032,.F.);
#1286=DIRECTION('',(0.577350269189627,-0.577350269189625,0.577350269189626));
#1287=VECTOR('',#1286,1.);
#1288=CARTESIAN_POINT('',(6.3333333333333,40.6666666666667,-3.66666666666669));
#1289=LINE('',#1288,#1287);
#1290=EDGE_CURVE('E506',#984,#1025,#1289,.F.);
#1291=ORIENTED_EDGE('',*,*,#1290,.F.);
#1292=ORIENTED_EDGE('',*,*,#985,.F.);
#1293=EDGE_LOOP('',(#1284,#1285,#1291,#1292));
#1294=FACE_BOUND('',#1293,.T.);
#1295=ADVANCED_FACE('F227',(#1294),#1278,.F.);
#1296=CARTESIAN_POINT('',(-19.,28.,9.));
#1297=DIRECTION('',(0.,0.707106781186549,0.707106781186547));
#1298=DIRECTION('',(0.,-0.707106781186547,0.707106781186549));
#1299=AXIS2_PLACEMENT_3D('',#1296,#1297,#1298);
#1300=PLANE('',#1299);
#1301=ORIENTED_EDGE('',*,*,#1290,.T.);
#1302=ORIENTED_EDGE('',*,*,#1026,.F.);
#1303=DIRECTION('',(0.577350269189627,0.577350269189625,-0.577350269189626));
#1304=VECTOR('',#1303,1.);
#1305=CARTESIAN_POINT('',(-19.,28.,9.));
#1306=LINE('',#1305,#1304);
#1307=EDGE_CURVE('E497',#150,#1017,#1306,.T.);
#1308=ORIENTED_EDGE('',*,*,#1307,.F.);
#1309=ORIENTED_EDGE('',*,*,#1058,.F.);
#1310=EDGE_LOOP('',(#1301,#1302,#1308,#1309));
#1311=FACE_BOUND('',#1310,.T.);
#1312=ADVANCED_FACE('F235',(#1311),#1300,.T.);
#1313=CARTESIAN_POINT('',(-19.,30.,-7.));
#1314=DIRECTION('',(0.,-0.707106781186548,0.707106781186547));
#1315=DIRECTION('',(0.,-0.707106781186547,-0.707106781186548));
#1316=AXIS2_PLACEMENT_3D('',#1313,#1314,#1315);
#1317=PLANE('',#1316);
#1318=ORIENTED_EDGE('',*,*,#1283,.T.);
#1319=ORIENTED_EDGE('',*,*,#1099,.F.);
#1320=DIRECTION('',(0.577350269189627,0.577350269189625,0.577350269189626));
#1321=VECTOR('',#1320,1.);
#1322=CARTESIAN_POINT('',(-17.6666666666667,29.3333333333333,-7.66666666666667));
#1323=LINE('',#1322,#1321);
#1324=EDGE_CURVE('E495',#1009,#160,#1323,.F.);
#1325=ORIENTED_EDGE('',*,*,#1324,.F.);
#1326=ORIENTED_EDGE('',*,*,#1010,.F.);
#1327=EDGE_LOOP('',(#1318,#1319,#1325,#1326));
#1328=FACE_BOUND('',#1327,.T.);
#1329=ADVANCED_FACE('F500',(#1328),#1317,.F.);
#1330=CARTESIAN_POINT('',(-19.,28.,9.));
#1331=DIRECTION('',(0.707106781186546,-0.707106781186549,0.));
#1332=DIRECTION('',(0.707106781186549,0.707106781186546,0.));
#1333=AXIS2_PLACEMENT_3D('',#1330,#1331,#1332);
#1334=PLANE('',#1333);
#1335=ORIENTED_EDGE('',*,*,#1307,.T.);
#1336=ORIENTED_EDGE('',*,*,#1018,.F.);
#1337=ORIENTED_EDGE('',*,*,#1324,.T.);
#1338=ORIENTED_EDGE('',*,*,#161,.F.);
#1339=EDGE_LOOP('',(#1335,#1336,#1337,#1338));
#1340=FACE_BOUND('',#1339,.T.);
#1341=ADVANCED_FACE('F493',(#1340),#1334,.F.);
#1342=CLOSED_SHELL('',(#136,#179,#210,#241,#272,#303,#334,#365,#396,#427,#458,#489,#520,#551,
#582,#613,#644,#675,#706,#737,#768,#799,#830,#861,#892,#923,#954,#996,#1047,#1088,#1129,#1234,
#1260,#1273,#1295,#1312,#1329,#1341));
#1343=MANIFOLD_SOLID_BREP('B2',#1342);
#1344=ADVANCED_BREP_SHAPE_REPRESENTATION('',(#18,#1343),#14);
#1345=SHAPE_DEFINITION_REPRESENTATION(#9,#1344);
ENDSEC;
END-ISO-10303-21;
